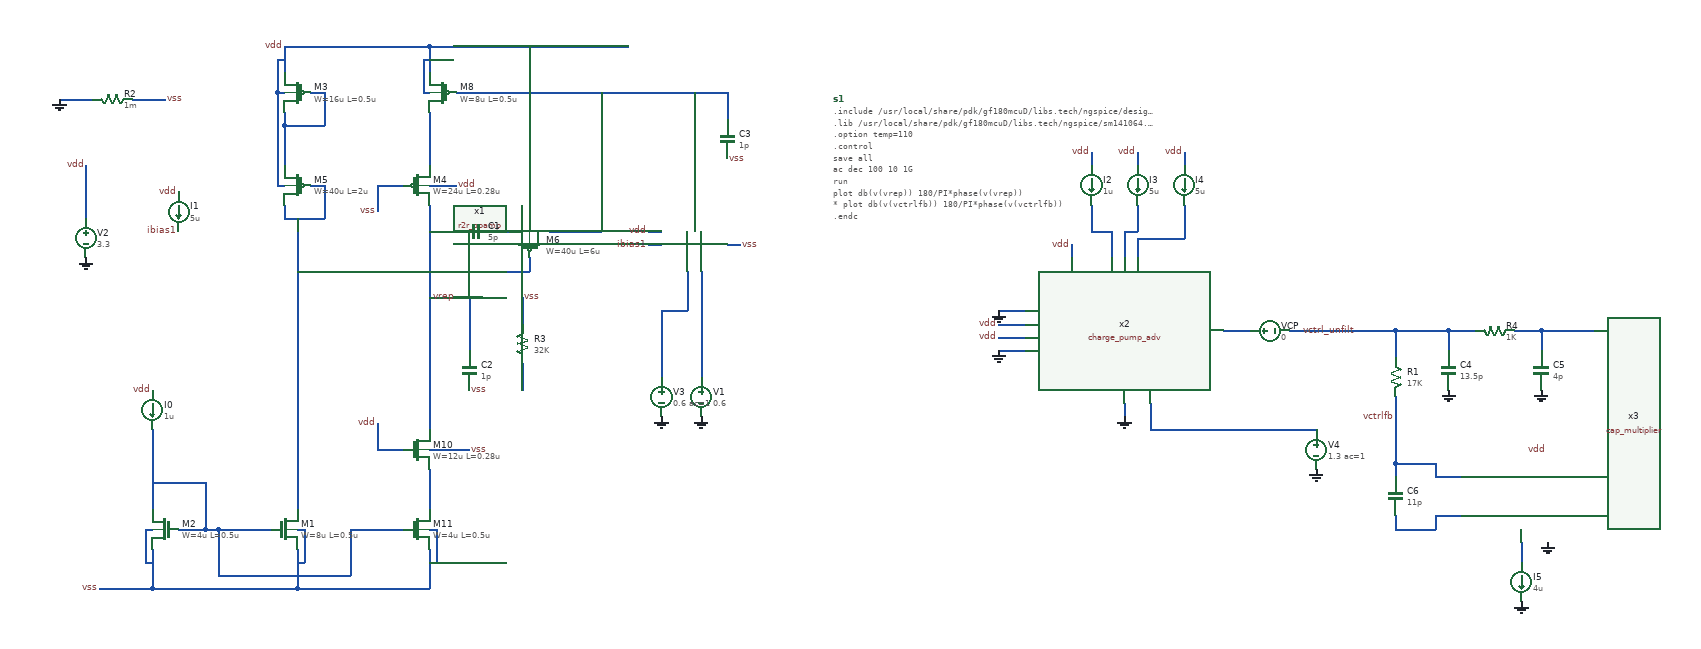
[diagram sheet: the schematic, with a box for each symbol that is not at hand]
v {xschem version=3.4.5 file_version=1.2
}
G {}
K {}
V {}
S {}
E {}
N 340 -640 340 -520 {
lab=#net1}
N 340 -460 340 -400 {
lab=vss}
N 330 -490 340 -490 {
lab=vss}
N 330 -490 330 -440 {
lab=vss}
N 330 -440 340 -440 {
lab=vss}
N 260 -400 340 -400 {
lab=vss}
N 760 -1220 760 -1180 {
lab=vdd}
N 750 -1150 760 -1150 {
lab=vdd}
N 750 -1200 750 -1150 {
lab=vdd}
N 750 -1200 760 -1200 {
lab=vdd}
N 800 -1150 860 -1150 {
lab=#net2}
N 760 -1220 860 -1220 {
lab=vdd}
N 660 -1220 760 -1220 {
lab=vdd}
N 860 -1220 1060 -1220 {
lab=vdd}
N 1010 -1150 1210 -1150 {
lab=#net2}
N 1160 -1150 1160 -1000 {
lab=#net2}
N 760 -1010 770 -1010 {
lab=vdd}
N 760 -610 820 -610 {
lab=vss}
N 760 -980 760 -640 {
lab=vrep}
N 760 -1120 760 -1040 {
lab=#net3}
N 680 -490 720 -490 {
lab=#net1}
N 760 -460 760 -400 {
lab=vss}
N 760 -490 770 -490 {
lab=vss}
N 770 -490 770 -440 {
lab=vss}
N 760 -440 770 -440 {
lab=vss}
N 760 -560 760 -520 {
lab=#net4}
N 760 -580 760 -560 {
lab=#net4}
N 680 -610 720 -610 {
lab=vdd}
N 680 -650 680 -610 {
lab=vdd}
N 680 -1010 720 -1010 {
lab=vss}
N 680 -1010 680 -970 {
lab=vss}
N 1150 -880 1150 -840 {
lab=#net5}
N 1170 -880 1170 -840 {
lab=#net6}
N 560 -400 760 -400 {
lab=vss}
N 340 -560 420 -560 {
lab=#net1}
N 420 -560 420 -490 {
lab=#net1}
N 380 -490 420 -490 {
lab=#net1}
N 640 -490 680 -490 {
lab=#net1}
N 1090 -940 1110 -940 {
lab=vdd}
N 1090 -920 1110 -920 {
lab=ibias1}
N 1210 -920 1230 -920 {
lab=vss}
N 1170 -840 1170 -720 {
lab=#net6}
N 760 -840 840 -840 {
lab=vrep}
N 770 -1010 800 -1010 {
lab=vdd}
N 900 -740 900 -700 {
lab=#net7}
N 240 -1040 240 -960 {
lab=vdd}
N 200 -1140 250 -1140 {
lab=GND}
N 310 -1140 360 -1140 {
lab=vss}
N 1110 -820 1110 -720 {
lab=#net5}
N 1110 -820 1150 -820 {
lab=#net5}
N 1150 -840 1150 -820 {
lab=#net5}
N 1210 -1150 1210 -1110 {
lab=#net2}
N 340 -400 560 -400 {
lab=vss}
N 480 -490 520 -490 {
lab=#net1}
N 560 -460 560 -400 {
lab=vss}
N 560 -490 570 -490 {
lab=vss}
N 570 -490 570 -440 {
lab=vss}
N 560 -440 570 -440 {
lab=vss}
N 560 -560 560 -520 {
lab=#net8}
N 440 -490 480 -490 {
lab=#net1}
N 420 -490 440 -490 {
lab=#net1}
N 440 -490 440 -420 {
lab=#net1}
N 440 -420 640 -420 {
lab=#net1}
N 640 -490 640 -420 {
lab=#net1}
N 540 -1220 540 -1180 {
lab=vdd}
N 530 -1150 540 -1150 {
lab=vdd}
N 530 -1200 530 -1150 {
lab=vdd}
N 530 -1200 540 -1200 {
lab=vdd}
N 540 -1220 660 -1220 {
lab=vdd}
N 540 -1120 540 -1100 {
lab=#net9}
N 540 -1100 600 -1100 {
lab=#net9}
N 600 -1150 600 -1100 {
lab=#net9}
N 580 -1150 600 -1150 {
lab=#net9}
N 530 -1010 540 -1010 {
lab=vdd}
N 540 -980 540 -960 {
lab=#net8}
N 540 -960 600 -960 {
lab=#net8}
N 600 -1010 600 -960 {
lab=#net8}
N 580 -1010 600 -1010 {
lab=#net8}
N 540 -1100 540 -1040 {
lab=#net9}
N 530 -1150 530 -1010 {
lab=vdd}
N 560 -960 560 -560 {
lab=#net8}
N 860 -1150 1010 -1150 {
lab=#net2}
N 940 -940 1020 -940 {
lab=#net2}
N 910 -1220 910 -940 {
lab=vdd}
N 910 -900 910 -880 {
lab=#net8}
N 560 -880 910 -880 {
lab=#net8}
N 760 -940 800 -940 {
lab=vrep}
N 860 -940 880 -940 {
lab=#net10}
N 1020 -1150 1020 -940 {
lab=#net2}
N 1760 -980 1760 -940 {
lab=#net11}
N 1760 -1060 1760 -1040 {
lab=vdd}
N 1760 -940 1790 -940 {
lab=#net11}
N 1790 -940 1790 -900 {
lab=#net11}
N 1730 -920 1730 -900 {
lab=vdd}
N 1830 -1060 1830 -1040 {
lab=vdd}
N 1900 -1060 1900 -1040 {
lab=vdd}
N 1830 -980 1830 -940 {
lab=#net12}
N 1810 -940 1830 -940 {
lab=#net12}
N 1810 -940 1810 -900 {
lab=#net12}
N 1900 -980 1900 -930 {
lab=#net13}
N 1830 -930 1900 -930 {
lab=#net13}
N 1830 -930 1830 -900 {
lab=#net13}
N 1810 -680 1810 -660 {
lab=GND}
N 1850 -680 1850 -640 {
lab=#net14}
N 2060 -790 2100 -790 {
lab=vctrl_unfilt}
N 1960 -790 2000 -790 {
lab=#net15}
N 1850 -640 2100 -640 {
lab=#net14}
N 2410 -470 2410 -440 {
lab=#net16}
N 2220 -590 2220 -570 {
lab=vctrlfb}
N 2220 -590 2280 -590 {
lab=vctrlfb}
N 2280 -590 2280 -570 {
lab=vctrlfb}
N 2280 -570 2320 -570 {
lab=vctrlfb}
N 2220 -510 2220 -490 {
lab=#net17}
N 2220 -490 2280 -490 {
lab=#net17}
N 2280 -510 2280 -490 {
lab=#net17}
N 2280 -510 2320 -510 {
lab=#net17}
N 2220 -790 2220 -750 {
lab=vctrl_unfilt}
N 2220 -690 2220 -590 {
lab=vctrlfb}
N 2100 -790 2220 -790 {
lab=vctrl_unfilt}
N 2300 -790 2300 -760 {
lab=vctrl_unfilt}
N 2220 -790 2300 -790 {
lab=vctrl_unfilt}
N 2300 -790 2340 -790 {
lab=vctrl_unfilt}
N 2400 -790 2440 -790 {
lab=#net18}
N 2440 -790 2440 -760 {
lab=#net18}
N 2440 -790 2500 -790 {
lab=#net18}
N 2500 -790 2520 -790 {
lab=#net18}
N 1620 -820 1660 -820 {
lab=GND}
N 1620 -800 1660 -800 {
lab=vdd}
N 1620 -780 1660 -780 {
lab=vdd}
N 1620 -760 1660 -760 {
lab=GND}
N 900 -840 900 -800 {
lab=vss}
N 820 -840 820 -760 {
lab=vrep}
C {symbols/nfet_03v3.sym} 360 -490 0 1 {name=M2
L=0.5u
W=4u
nf=1
m=1
ad="'int((nf+1)/2) * W/nf * 0.18u'"
pd="'2*int((nf+1)/2) * (W/nf + 0.18u)'"
as="'int((nf+2)/2) * W/nf * 0.18u'"
ps="'2*int((nf+2)/2) * (W/nf + 0.18u)'"
nrd="'0.18u / W'" nrs="'0.18u / W'"
sa=0 sb=0 sd=0
model=nfet_03v3
spiceprefix=X
}
C {symbols/pfet_03v3.sym} 780 -1150 0 1 {name=M8
L=0.5u
W=8u
nf=1
m=1
ad="'int((nf+1)/2) * W/nf * 0.18u'"
pd="'2*int((nf+1)/2) * (W/nf + 0.18u)'"
as="'int((nf+2)/2) * W/nf * 0.18u'"
ps="'2*int((nf+2)/2) * (W/nf + 0.18u)'"
nrd="'0.18u / W'" nrs="'0.18u / W'"
sa=0 sb=0 sd=0
model=pfet_03v3
spiceprefix=X
}
C {r2r_opamp.sym} 1210 -880 3 0 {name=x1}
C {symbols/pfet_03v3.sym} 740 -1010 0 0 {name=M4
L=0.28u
W=24u
nf=1
m=1
ad="'int((nf+1)/2) * W/nf * 0.18u'"
pd="'2*int((nf+1)/2) * (W/nf + 0.18u)'"
as="'int((nf+2)/2) * W/nf * 0.18u'"
ps="'2*int((nf+2)/2) * (W/nf + 0.18u)'"
nrd="'0.18u / W'" nrs="'0.18u / W'"
sa=0 sb=0 sd=0
model=pfet_03v3
spiceprefix=X
}
C {symbols/nfet_03v3.sym} 740 -610 0 0 {name=M10
L=0.28u
W=12u
nf=1
m=1
ad="'int((nf+1)/2) * W/nf * 0.18u'"
pd="'2*int((nf+1)/2) * (W/nf + 0.18u)'"
as="'int((nf+2)/2) * W/nf * 0.18u'"
ps="'2*int((nf+2)/2) * (W/nf + 0.18u)'"
nrd="'0.18u / W'" nrs="'0.18u / W'"
sa=0 sb=0 sd=0
model=nfet_03v3
spiceprefix=X
}
C {symbols/nfet_03v3.sym} 740 -490 0 0 {name=M11
L=0.5u
W=4u
nf=1
m=1
ad="'int((nf+1)/2) * W/nf * 0.18u'"
pd="'2*int((nf+1)/2) * (W/nf + 0.18u)'"
as="'int((nf+2)/2) * W/nf * 0.18u'"
ps="'2*int((nf+2)/2) * (W/nf + 0.18u)'"
nrd="'0.18u / W'" nrs="'0.18u / W'"
sa=0 sb=0 sd=0
model=nfet_03v3
spiceprefix=X
}
C {lab_pin.sym} 680 -970 3 0 {name=p3 sig_type=std_logic lab=vss}
C {lab_pin.sym} 680 -650 1 0 {name=p4 sig_type=std_logic lab=vdd}
C {lab_pin.sym} 1230 -920 2 0 {name=p6 sig_type=std_logic lab=vss}
C {lab_pin.sym} 1090 -940 0 0 {name=p7 sig_type=std_logic lab=vdd}
C {lab_pin.sym} 1090 -920 0 0 {name=p8 sig_type=std_logic lab=ibias1}
C {lab_pin.sym} 820 -610 2 0 {name=p25 sig_type=std_logic lab=vss}
C {lab_pin.sym} 800 -1010 0 1 {name=p26 sig_type=std_logic lab=vdd}
C {lab_wire.sym} 800 -840 0 0 {name=p34 sig_type=std_logic lab=vrep}
C {capa.sym} 820 -730 0 0 {name=C2
m=1
value=1p
footprint=1206
device="ceramic capacitor"}
C {lab_pin.sym} 820 -700 2 0 {name=p35 sig_type=std_logic lab=vss}
C {lab_pin.sym} 260 -400 2 1 {name=p1 sig_type=std_logic lab=vss}
C {lab_pin.sym} 540 -1220 0 0 {name=p2 sig_type=std_logic lab=vdd}
C {vsource.sym} 1170 -690 0 0 {name=V1 value="0.6" savecurrent=false}
C {gnd.sym} 1170 -660 0 0 {name=l1 lab=GND}
C {isource.sym} 340 -670 0 0 {name=I0 value=1u}
C {vsource.sym} 240 -930 0 0 {name=V2 value=3.3 savecurrent=false}
C {gnd.sym} 240 -900 0 0 {name=l2 lab=GND}
C {lab_pin.sym} 240 -1040 1 0 {name=p5 sig_type=std_logic lab=vdd}
C {lab_pin.sym} 340 -700 1 0 {name=p9 sig_type=std_logic lab=vdd}
C {res.sym} 280 -1140 1 0 {name=R2
value=1m
footprint=1206
device=resistor
m=1}
C {lab_pin.sym} 360 -1140 2 0 {name=p10 sig_type=std_logic lab=vss}
C {gnd.sym} 200 -1140 0 0 {name=l3 lab=GND}
C {vsource.sym} 1110 -690 0 0 {name=V3 value="0.6 ac=1" savecurrent=false}
C {isource.sym} 380 -970 0 0 {name=I1 value=5u}
C {lab_pin.sym} 380 -1000 1 0 {name=p11 sig_type=std_logic lab=vdd}
C {lab_pin.sym} 380 -940 3 0 {name=p12 sig_type=std_logic lab=ibias1}
C {gnd.sym} 1110 -660 0 0 {name=l4 lab=GND}
C {code.sym} 1370 -1140 0 0 {name=s1 only_toplevel=false value="
.include /usr/local/share/pdk/gf180mcuD/libs.tech/ngspice/design.ngspice
.lib /usr/local/share/pdk/gf180mcuD/libs.tech/ngspice/sm141064.ngspice ss
.option temp=110

.control
save all

ac dec 100 10 1G
run
plot db(v(vrep)) 180/PI*phase(v(vrep))
* plot db(v(vctrlfb)) 180/PI*phase(v(vctrlfb))

.endc
"}
C {capa.sym} 1210 -1080 0 0 {name=C3
m=1
value=1p
footprint=1206
device="ceramic capacitor"}
C {lab_pin.sym} 1210 -1050 2 0 {name=p13 sig_type=std_logic lab=vss}
C {symbols/nfet_03v3.sym} 540 -490 0 0 {name=M1
L=0.5u
W=8u
nf=1
m=1
ad="'int((nf+1)/2) * W/nf * 0.18u'"
pd="'2*int((nf+1)/2) * (W/nf + 0.18u)'"
as="'int((nf+2)/2) * W/nf * 0.18u'"
ps="'2*int((nf+2)/2) * (W/nf + 0.18u)'"
nrd="'0.18u / W'" nrs="'0.18u / W'"
sa=0 sb=0 sd=0
model=nfet_03v3
spiceprefix=X
}
C {symbols/pfet_03v3.sym} 560 -1150 0 1 {name=M3
L=0.5u
W=16u
nf=1
m=1
ad="'int((nf+1)/2) * W/nf * 0.18u'"
pd="'2*int((nf+1)/2) * (W/nf + 0.18u)'"
as="'int((nf+2)/2) * W/nf * 0.18u'"
ps="'2*int((nf+2)/2) * (W/nf + 0.18u)'"
nrd="'0.18u / W'" nrs="'0.18u / W'"
sa=0 sb=0 sd=0
model=pfet_03v3
spiceprefix=X
}
C {symbols/pfet_03v3.sym} 560 -1010 0 1 {name=M5
L=2u
W=40u
nf=1
m=1
ad="'int((nf+1)/2) * W/nf * 0.18u'"
pd="'2*int((nf+1)/2) * (W/nf + 0.18u)'"
as="'int((nf+2)/2) * W/nf * 0.18u'"
ps="'2*int((nf+2)/2) * (W/nf + 0.18u)'"
nrd="'0.18u / W'" nrs="'0.18u / W'"
sa=0 sb=0 sd=0
model=pfet_03v3
spiceprefix=X
}
C {symbols/pfet_03v3.sym} 910 -920 1 1 {name=M6
L=6u
W=40u
nf=1
m=1
ad="'int((nf+1)/2) * W/nf * 0.18u'"
pd="'2*int((nf+1)/2) * (W/nf + 0.18u)'"
as="'int((nf+2)/2) * W/nf * 0.18u'"
ps="'2*int((nf+2)/2) * (W/nf + 0.18u)'"
nrd="'0.18u / W'" nrs="'0.18u / W'"
sa=0 sb=0 sd=0
model=pfet_03v3
spiceprefix=X
}
C {capa.sym} 830 -940 3 1 {name=C1
m=1
value=5p
footprint=1206
device="ceramic capacitor"}
C {isource.sym} 1760 -1010 0 0 {name=I2 value=1u}
C {lab_pin.sym} 1760 -1060 1 0 {name=p14 sig_type=std_logic lab=vdd}
C {lab_pin.sym} 2160 -790 3 0 {name=p15 sig_type=std_logic lab=vctrl_unfilt}
C {lab_pin.sym} 1730 -920 1 0 {name=p16 sig_type=std_logic lab=vdd}
C {isource.sym} 1830 -1010 0 0 {name=I3 value=5u}
C {isource.sym} 1900 -1010 0 0 {name=I4 value=5u}
C {lab_pin.sym} 1830 -1060 1 0 {name=p23 sig_type=std_logic lab=vdd}
C {lab_pin.sym} 1900 -1060 1 0 {name=p24 sig_type=std_logic lab=vdd}
C {gnd.sym} 1810 -660 0 0 {name=l5 lab=GND}
C {charge_pump_adv.sym} 1810 -790 0 0 {name=x2}
C {vsource.sym} 2030 -790 3 0 {name=VCP value=0 savecurrent=true}
C {cap_multiplier.sym} 2470 -540 0 0 {name=x3}
C {isource.sym} 2410 -410 0 0 {name=I5 value=4u}
C {gnd.sym} 2450 -470 0 0 {name=l10 lab=GND}
C {gnd.sym} 2410 -380 0 0 {name=l11 lab=GND}
C {capa.sym} 2220 -540 0 0 {name=C6
m=1
value=11p
footprint=1206
device="ceramic capacitor"}
C {res.sym} 2220 -720 0 0 {name=R1
value=17K
footprint=1206
device=resistor
m=1}
C {capa.sym} 2300 -730 0 0 {name=C4
m=1
value=13.5p
footprint=1206
device="ceramic capacitor"}
C {gnd.sym} 2300 -700 0 0 {name=l6 lab=GND}
C {res.sym} 2370 -790 1 0 {name=R4
value=1K
footprint=1206
device=resistor
m=1}
C {capa.sym} 2440 -730 0 0 {name=C5
m=1
value=4p
footprint=1206
device="ceramic capacitor"}
C {gnd.sym} 2440 -700 0 0 {name=l7 lab=GND}
C {lab_pin.sym} 2450 -610 1 0 {name=p17 sig_type=std_logic lab=vdd}
C {lab_pin.sym} 1620 -800 0 0 {name=p18 sig_type=std_logic lab=vdd}
C {gnd.sym} 1620 -820 1 0 {name=l8 lab=GND}
C {lab_pin.sym} 1620 -780 0 0 {name=p19 sig_type=std_logic lab=vdd}
C {gnd.sym} 1620 -760 1 0 {name=l9 lab=GND}
C {lab_pin.sym} 2220 -660 0 0 {name=p20 sig_type=std_logic lab=vctrlfb}
C {vsource.sym} 2100 -610 0 0 {name=V4 value="1.3 ac=1" savecurrent=false}
C {gnd.sym} 2100 -580 0 0 {name=l12 lab=GND}
C {res.sym} 900 -770 2 0 {name=R3
value=32K
footprint=1206
device=resistor
m=1}
C {lab_pin.sym} 900 -840 2 0 {name=p21 sig_type=std_logic lab=vss}
